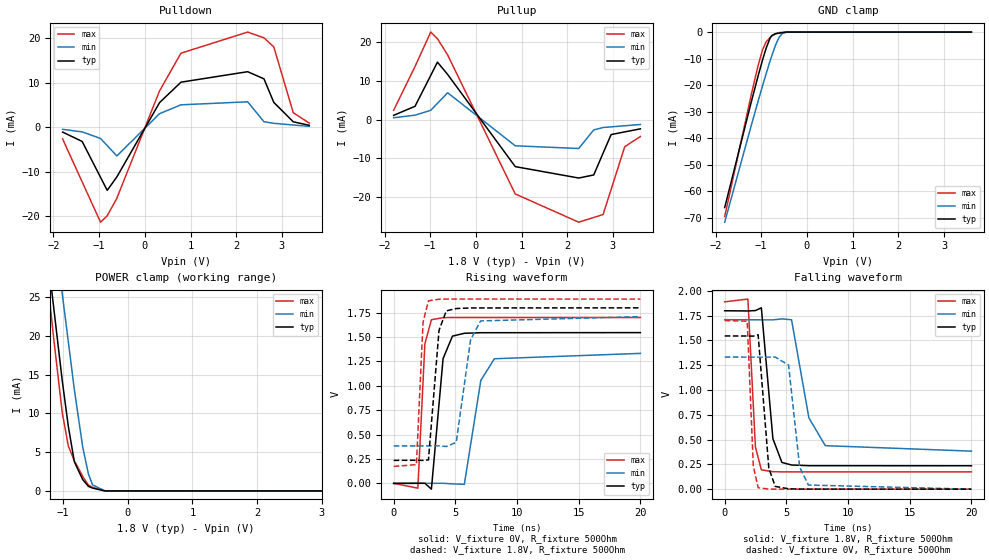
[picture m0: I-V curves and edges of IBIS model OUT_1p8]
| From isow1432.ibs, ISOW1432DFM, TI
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|   OUT_1p8 Model
[Model]   OUT_1p8
Model_type   3-state
Polarity   Inverting
Vmeas = 0.9
Vref = 0
Cref = 2pF
Rref = 100000
|   typ   min   max
C_comp   1.293pF   1.246pF   1.386pF
|  Where Nom  PVT is Nominal Process, 1.8V,  27C
|   Fast PVT is Strong Process,  1.89, -40C
|   Slow PVT is Weak Process,   1.71V, 150C
[Voltage Range]   1.8   1.71   1.89
|Junction Temperature
[Temperature Range]   27   150   -40
[Pullup Reference]   1.8   1.71   1.89
[Pulldown Reference]   -0   0   -0
[Power Clamp Reference]   1.8   1.71   1.89
[GND Clamp Reference]   0   0   0
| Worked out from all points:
|   slope of the pulldown table from 0 to 0.27 V, typ, clamps not added: 57.1 ohm
|   slope of the pullup table from 0 to 0.27 V, typ, clamps not added: 56 ohm
|   GND clamp passes 1 mA (typ) near -0.75 V on its own axis
|   POWER clamp passes 1 mA (typ) near -0.65 V on its own axis
|   falling waveform, V_fixture 1.8V, R_fixture 500Ohm: 20-80 % time 594ps typ, 1.2ns min, 367ps max; typ from 1.8 V to 0.236 V
|   rising waveform, V_fixture 0V, R_fixture 500Ohm: 20-80 % time 519ps typ, 948ps min, 328ps max; typ from 0 V to 1.55 V
|   rising waveform, V_fixture 1.8V, R_fixture 500Ohm: 20-80 % time 487ps typ, 868ps min, 305ps max; typ from 0.236 V to 1.8 V
|   falling waveform, V_fixture 0V, R_fixture 500Ohm: 20-80 % time 419ps typ, 641ps min, 297ps max; typ from 1.55 V to 0 V
[Pulldown]
|   Voltage   I(typ)   I(min)   I(max)
-1.8V     -1.084mA   -473.2uA   -2.619mA
-1.372V   -3.194mA   -1.042mA   -12.25mA
-970.1mV  -11.23mA   -2.516mA   -21.29mA
-823.7mV  -14.15mA   -4.125mA   -19.85mA
-613.1mV  -11.14mA   -6.44mA    -15.94mA
321.3mV   5.51mA     3.039mA    8.138mA
790.7mV   10.1mA     5.023mA    16.6mA
2.25V     12.45mA    5.701mA    21.33mA
2.607V    10.85mA    1.238mA    20.05mA
2.822V    5.573mA    872.8uA    18.01mA
3.248V    1.217mA    501.2uA    3.262mA
3.6V      424.3uA    193.8uA    911.9uA
[GND Clamp]
|   Voltage   I(typ)   I(min)   I(max)
-1.8V     -66.17mA   -71.69mA   -69.59mA
-1.222V   -26.61mA   -35.44mA   -23.87mA
-1.071V   -16.68mA   -26.16mA   -12.77mA
-972.9mV  -10.58mA   -20.31mA   -6.741mA
-892mV    -6.036mA   -15.67mA   -3.651mA
-802.3mV  -2.066mA   -10.64mA   -2.027mA
-766.2mV  -1.327mA   -8.794mA   -1.375mA
-687.9mV  -577.7uA   -4.937mA   -700.9uA
-607.9mV  -384.2uA   -1.942mA   -204.8uA
-539.2mV  -218uA     -539.4uA   -117uA
-449.9mV  -2.005uA   -59.78uA   -2.825uA
3.6V      0A         0A         0A
[Pullup]
|   Voltage   I(typ)   I(min)   I(max)
-1.8V     1.106mA    489.9uA    2.428mA
-1.332V   3.455mA    1.15mA     13.75mA
-988.5mV  11.45mA    2.41mA     22.65mA
-841.3mV  14.88mA    4.213mA    20.95mA
-617.7mV  11.68mA    6.952mA    16.72mA
861.2mV   -12.16mA   -6.775mA   -19.23mA
2.25V     -15.11mA   -7.468mA   -26.54mA
2.579V    -14.32mA   -2.671mA   -25.32mA
2.784V    -8.67mA    -2.04mA    -24.56mA
2.96V     -3.861mA   -1.872mA   -18.06mA
3.258V    -3.173mA   -1.586mA   -6.994mA
3.6V      -2.387mA   -1.259mA   -4.389mA
[POWER Clamp]
-1.8V     73.64mA    80.72mA    75.63mA
-1.242V   30.77mA    40.89mA    27.23mA
-1.188V   26.64mA    37.05mA    22.93mA
-1.162V   24.73mA    35.15mA    20.8mA
-1.015V   14.25mA    25.48mA    10.09mA
-920.6mV  8.33mA     19.22mA    5.79mA
-828mV    3.775mA    13.11mA    3.905mA
-698.9mV  1.476mA    5.701mA    1.892mA
-610.3mV  590.3uA    2.206mA    755.6uA
-546mV    369.9uA    774.3uA    454uA
-355.8mV  4.932uA    20.1uA     2.334uA
3.6V      0A         0A         0A
[Ramp]
R_load = 500
|   typ   min   max
dV/dt_r   0.927695/5.15062e-10   0.799772/9.45208e-10   1.02082/3.27709e-10
dV/dt_f   0.938426/5.92453e-10   0.795755/1.19026e-09   1.0295/3.6509e-10
[Falling Waveform]
V_fixture = 1.8V
V_fixture_min = 1.71V
V_fixture_max = 1.89V
R_fixture = 500Ohm
C_fixture = 0F
|   Time   V(typ)   V(min)   V(max)
0s        1.8V       1.71V      1.89V
1.881ns   1.798V     1.709V     1.918V
2.491ns   1.802V     1.709V     425.2mV
2.971ns   1.83V      1.708V     194.9mV
3.907ns   510mV      1.708V     176.3mV
4.637ns   269.7mV    1.718V     174.6mV
5.419ns   243.8mV    1.709V     174.6mV
6.826ns   237mV      718.8mV    174.6mV
8.156ns   236.9mV    438.9mV    174.5mV
20ns      236mV      383.7mV    174.2mV
[Rising Waveform]
V_fixture = 0V
V_fixture_min = 0V
V_fixture_max = 0V
R_fixture = 500Ohm
C_fixture = 0F
|   Time   V(typ)   V(min)   V(max)
0s        -701.1nV   1.066uV    -3.78nV
1.962ns   1.104mV    579.3uV    -49.18mV
2.531ns   1.424mV    747.1uV    1.431V
3.061ns   -59.26mV   903.4uV    1.678V
4.007ns   1.28V      1.182mV    1.699V
4.767ns   1.51V      -4.802mV   1.701V
5.729ns   1.539V     -9.799mV   1.701V
7.066ns   1.545V     1.056V     1.701V
8.166ns   1.545V     1.278V     1.701V
20ns      1.546V     1.333V     1.701V
[Rising Waveform]
V_fixture = 1.8V
V_fixture_min = 1.71V
V_fixture_max = 1.89V
R_fixture = 500Ohm
C_fixture = 0F
|   Time   V(typ)   V(min)   V(max)
0s        236mV      383.7mV    174.2mV
1.846ns   237.1mV    384.3mV    192.2mV
2.381ns   235.7mV    384.4mV    1.652V
2.821ns   241mV      384.6mV    1.872V
3.677ns   1.569V     384.8mV    1.888V
4.267ns   1.769V     377.9mV    1.89V
5.071ns   1.793V     420.3mV    1.89V
6.237ns   1.799V     1.472V     1.89V
7.046ns   1.799V     1.666V     1.89V
20ns      1.8V       1.71V      1.89V
[Falling Waveform]
|Gnd
V_fixture = 0V
V_fixture_min = 0V
V_fixture_max = 0V
R_fixture = 500Ohm
C_fixture = 0F
|   Time   V(typ)   V(min)   V(max)
0s        1.546V     1.333V     1.701V
1.826ns   1.545V     1.332V     1.695V
2.321ns   1.544V     1.332V     231.8mV
2.711ns   1.558V     1.332V     14.28mV
3.577ns   211.6mV    1.332V     392.6uV
4.097ns   27.56mV    1.333V     227.1uV
5.179ns   3.966mV    1.252V     211.6uV
6.077ns   855.8uV    222.7mV    198.8uV
6.786ns   812.1uV    41.64mV    188.7uV
20ns      -138nV     980.3nV    -4.639nV
